VERSION 5.7 ;
  NOWIREEXTENSIONATPIN ON ;
  DIVIDERCHAR "/" ;
  BUSBITCHARS "[]" ;
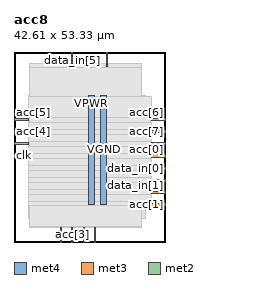
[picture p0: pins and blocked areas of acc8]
MACRO acc8
  CLASS BLOCK ;
  FOREIGN acc8 ;
  ORIGIN 0.000 0.000 ;
  SIZE 42.610 BY 53.330 ;
  PIN VGND
    DIRECTION INOUT ;
    USE GROUND ;
    PORT
      LAYER met4 ;
        RECT 24.340 10.640 25.940 41.040 ;
    END
  END VGND
  PIN VPWR
    DIRECTION INOUT ;
    USE POWER ;
    PORT
      LAYER met4 ;
        RECT 21.040 10.640 22.640 41.040 ;
    END
  END VPWR
  PIN acc[0]
    DIRECTION OUTPUT ;
    USE SIGNAL ;
    ANTENNADIFFAREA 0.445500 ;
    PORT
      LAYER met3 ;
        RECT 38.610 23.840 42.610 24.440 ;
    END
  END acc[0]
  PIN acc[1]
    DIRECTION OUTPUT ;
    USE SIGNAL ;
    ANTENNADIFFAREA 0.445500 ;
    PORT
      LAYER met3 ;
        RECT 38.610 10.240 42.610 10.840 ;
    END
  END acc[1]
  PIN acc[2]
    DIRECTION OUTPUT ;
    USE SIGNAL ;
    ANTENNADIFFAREA 0.445500 ;
    PORT
      LAYER met2 ;
        RECT 22.630 0.000 22.910 4.000 ;
    END
  END acc[2]
  PIN acc[3]
    DIRECTION OUTPUT ;
    USE SIGNAL ;
    ANTENNADIFFAREA 0.445500 ;
    PORT
      LAYER met2 ;
        RECT 16.190 0.000 16.470 4.000 ;
    END
  END acc[3]
  PIN acc[4]
    DIRECTION OUTPUT ;
    USE SIGNAL ;
    ANTENNADIFFAREA 0.445500 ;
    PORT
      LAYER met3 ;
        RECT 0.000 30.640 4.000 31.240 ;
    END
  END acc[4]
  PIN acc[5]
    DIRECTION OUTPUT ;
    USE SIGNAL ;
    ANTENNADIFFAREA 0.445500 ;
    PORT
      LAYER met3 ;
        RECT 0.000 34.040 4.000 34.640 ;
    END
  END acc[5]
  PIN acc[6]
    DIRECTION OUTPUT ;
    USE SIGNAL ;
    ANTENNADIFFAREA 0.445500 ;
    PORT
      LAYER met3 ;
        RECT 38.610 34.040 42.610 34.640 ;
    END
  END acc[6]
  PIN acc[7]
    DIRECTION OUTPUT ;
    USE SIGNAL ;
    ANTENNADIFFAREA 0.445500 ;
    PORT
      LAYER met3 ;
        RECT 38.610 30.640 42.610 31.240 ;
    END
  END acc[7]
  PIN clk
    DIRECTION INPUT ;
    USE SIGNAL ;
    ANTENNAGATEAREA 0.852000 ;
    PORT
      LAYER met3 ;
        RECT 0.000 23.840 4.000 24.440 ;
    END
  END clk
  PIN data_in[0]
    DIRECTION INPUT ;
    USE SIGNAL ;
    ANTENNAGATEAREA 0.196500 ;
    PORT
      LAYER met3 ;
        RECT 38.610 20.440 42.610 21.040 ;
    END
  END data_in[0]
  PIN data_in[1]
    DIRECTION INPUT ;
    USE SIGNAL ;
    ANTENNAGATEAREA 0.196500 ;
    PORT
      LAYER met3 ;
        RECT 38.610 13.640 42.610 14.240 ;
    END
  END data_in[1]
  PIN data_in[2]
    DIRECTION INPUT ;
    USE SIGNAL ;
    ANTENNAGATEAREA 0.196500 ;
    PORT
      LAYER met2 ;
        RECT 19.410 0.000 19.690 4.000 ;
    END
  END data_in[2]
  PIN data_in[3]
    DIRECTION INPUT ;
    USE SIGNAL ;
    ANTENNAGATEAREA 0.196500 ;
    PORT
      LAYER met2 ;
        RECT 12.970 0.000 13.250 4.000 ;
    END
  END data_in[3]
  PIN data_in[4]
    DIRECTION INPUT ;
    USE SIGNAL ;
    ANTENNAGATEAREA 0.196500 ;
    PORT
      LAYER met3 ;
        RECT 0.000 27.240 4.000 27.840 ;
    END
  END data_in[4]
  PIN data_in[5]
    DIRECTION INPUT ;
    USE SIGNAL ;
    ANTENNAGATEAREA 0.196500 ;
    PORT
      LAYER met2 ;
        RECT 16.190 49.330 16.470 53.330 ;
    END
  END data_in[5]
  PIN data_in[6]
    DIRECTION INPUT ;
    USE SIGNAL ;
    ANTENNAGATEAREA 0.196500 ;
    PORT
      LAYER met2 ;
        RECT 25.850 49.330 26.130 53.330 ;
    END
  END data_in[6]
  PIN data_in[7]
    DIRECTION INPUT ;
    USE SIGNAL ;
    ANTENNAGATEAREA 0.196500 ;
    PORT
      LAYER met3 ;
        RECT 38.610 27.240 42.610 27.840 ;
    END
  END data_in[7]
  PIN rst
    DIRECTION INPUT ;
    USE SIGNAL ;
    ANTENNAGATEAREA 0.213000 ;
    PORT
      LAYER met3 ;
        RECT 38.610 17.040 42.610 17.640 ;
    END
  END rst
  OBS
      LAYER nwell ;
        RECT 5.330 10.795 36.990 40.990 ;
      LAYER li1 ;
        RECT 5.520 10.795 36.800 40.885 ;
      LAYER met1 ;
        RECT 4.210 6.500 36.800 41.040 ;
      LAYER met2 ;
        RECT 4.230 49.050 15.910 50.050 ;
        RECT 16.750 49.050 25.570 50.050 ;
        RECT 26.410 49.050 35.790 50.050 ;
        RECT 4.230 4.280 35.790 49.050 ;
        RECT 4.230 4.000 12.690 4.280 ;
        RECT 13.530 4.000 15.910 4.280 ;
        RECT 16.750 4.000 19.130 4.280 ;
        RECT 19.970 4.000 22.350 4.280 ;
        RECT 23.190 4.000 35.790 4.280 ;
      LAYER met3 ;
        RECT 3.990 35.040 38.610 40.965 ;
        RECT 4.400 33.640 38.210 35.040 ;
        RECT 3.990 31.640 38.610 33.640 ;
        RECT 4.400 30.240 38.210 31.640 ;
        RECT 3.990 28.240 38.610 30.240 ;
        RECT 4.400 26.840 38.210 28.240 ;
        RECT 3.990 24.840 38.610 26.840 ;
        RECT 4.400 23.440 38.210 24.840 ;
        RECT 3.990 21.440 38.610 23.440 ;
        RECT 3.990 20.040 38.210 21.440 ;
        RECT 3.990 18.040 38.610 20.040 ;
        RECT 3.990 16.640 38.210 18.040 ;
        RECT 3.990 14.640 38.610 16.640 ;
        RECT 3.990 13.240 38.210 14.640 ;
        RECT 3.990 11.240 38.610 13.240 ;
        RECT 3.990 10.375 38.210 11.240 ;
  END
END acc8
END LIBRARY

